VERSION 5.7 ;
  NOWIREEXTENSIONATPIN ON ;
  DIVIDERCHAR "/" ;
  BUSBITCHARS "[]" ;
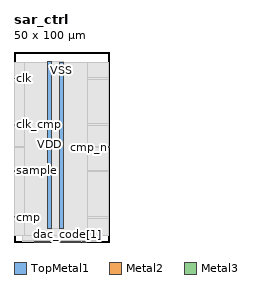
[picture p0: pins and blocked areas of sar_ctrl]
MACRO sar_ctrl
  CLASS BLOCK ;
  FOREIGN sar_ctrl ;
  ORIGIN 0.000 0.000 ;
  SIZE 50.000 BY 100.000 ;
  PIN VDD
    DIRECTION INOUT ;
    USE POWER ;
    PORT
      LAYER TopMetal1 ;
        RECT 17.780 7.340 19.980 95.130 ;
    END
  END VDD
  PIN VSS
    DIRECTION INOUT ;
    USE GROUND ;
    PORT
      LAYER TopMetal1 ;
        RECT 23.980 6.930 26.180 94.720 ;
    END
  END VSS
  PIN busy
    DIRECTION OUTPUT ;
    USE SIGNAL ;
    ANTENNADIFFAREA 0.708600 ;
    PORT
      LAYER Metal2 ;
        RECT 21.400 0.000 21.800 0.400 ;
    END
  END busy
  PIN clk
    DIRECTION INPUT ;
    USE SIGNAL ;
    ANTENNAGATEAREA 1.450800 ;
    PORT
      LAYER Metal3 ;
        RECT 0.000 85.900 0.400 86.300 ;
    END
  END clk
  PIN clk_cmp
    DIRECTION OUTPUT ;
    USE SIGNAL ;
    ANTENNADIFFAREA 0.708600 ;
    PORT
      LAYER Metal3 ;
        RECT 0.000 61.540 0.400 61.940 ;
    END
  END clk_cmp
  PIN cmp
    DIRECTION INPUT ;
    USE SIGNAL ;
    ANTENNAGATEAREA 0.180700 ;
    PORT
      LAYER Metal3 ;
        RECT 0.000 12.820 0.400 13.220 ;
    END
  END cmp
  PIN cmp_n
    DIRECTION INPUT ;
    USE SIGNAL ;
    ANTENNAGATEAREA 0.180700 ;
    PORT
      LAYER Metal3 ;
        RECT 49.600 49.780 50.000 50.180 ;
    END
  END cmp_n
  PIN dac_code[0]
    DIRECTION OUTPUT ;
    USE SIGNAL ;
    ANTENNADIFFAREA 0.708600 ;
    PORT
      LAYER Metal2 ;
        RECT 29.080 0.000 29.480 0.400 ;
    END
  END dac_code[0]
  PIN dac_code[1]
    DIRECTION OUTPUT ;
    USE SIGNAL ;
    ANTENNADIFFAREA 0.708600 ;
    PORT
      LAYER Metal2 ;
        RECT 28.120 0.000 28.520 0.400 ;
    END
  END dac_code[1]
  PIN dac_code[2]
    DIRECTION OUTPUT ;
    USE SIGNAL ;
    ANTENNADIFFAREA 0.708600 ;
    PORT
      LAYER Metal2 ;
        RECT 27.160 0.000 27.560 0.400 ;
    END
  END dac_code[2]
  PIN dac_code[3]
    DIRECTION OUTPUT ;
    USE SIGNAL ;
    ANTENNADIFFAREA 0.708600 ;
    PORT
      LAYER Metal2 ;
        RECT 26.200 0.000 26.600 0.400 ;
    END
  END dac_code[3]
  PIN dac_code[4]
    DIRECTION OUTPUT ;
    USE SIGNAL ;
    ANTENNADIFFAREA 0.708600 ;
    PORT
      LAYER Metal2 ;
        RECT 25.240 0.000 25.640 0.400 ;
    END
  END dac_code[4]
  PIN dac_code[5]
    DIRECTION OUTPUT ;
    USE SIGNAL ;
    ANTENNADIFFAREA 0.708600 ;
    PORT
      LAYER Metal2 ;
        RECT 24.280 0.000 24.680 0.400 ;
    END
  END dac_code[5]
  PIN dac_code[6]
    DIRECTION OUTPUT ;
    USE SIGNAL ;
    ANTENNADIFFAREA 0.708600 ;
    PORT
      LAYER Metal2 ;
        RECT 23.320 0.000 23.720 0.400 ;
    END
  END dac_code[6]
  PIN dac_code[7]
    DIRECTION OUTPUT ;
    USE SIGNAL ;
    ANTENNADIFFAREA 0.708600 ;
    PORT
      LAYER Metal2 ;
        RECT 22.360 0.000 22.760 0.400 ;
    END
  END dac_code[7]
  PIN dac_code_n[0]
    DIRECTION OUTPUT ;
    USE SIGNAL ;
    ANTENNADIFFAREA 0.708600 ;
    PORT
      LAYER Metal2 ;
        RECT 36.760 0.000 37.160 0.400 ;
    END
  END dac_code_n[0]
  PIN dac_code_n[1]
    DIRECTION OUTPUT ;
    USE SIGNAL ;
    ANTENNADIFFAREA 0.708600 ;
    PORT
      LAYER Metal2 ;
        RECT 35.800 0.000 36.200 0.400 ;
    END
  END dac_code_n[1]
  PIN dac_code_n[2]
    DIRECTION OUTPUT ;
    USE SIGNAL ;
    ANTENNADIFFAREA 0.708600 ;
    PORT
      LAYER Metal2 ;
        RECT 34.840 0.000 35.240 0.400 ;
    END
  END dac_code_n[2]
  PIN dac_code_n[3]
    DIRECTION OUTPUT ;
    USE SIGNAL ;
    ANTENNADIFFAREA 0.708600 ;
    PORT
      LAYER Metal2 ;
        RECT 33.880 0.000 34.280 0.400 ;
    END
  END dac_code_n[3]
  PIN dac_code_n[4]
    DIRECTION OUTPUT ;
    USE SIGNAL ;
    ANTENNADIFFAREA 0.708600 ;
    PORT
      LAYER Metal2 ;
        RECT 32.920 0.000 33.320 0.400 ;
    END
  END dac_code_n[4]
  PIN dac_code_n[5]
    DIRECTION OUTPUT ;
    USE SIGNAL ;
    ANTENNADIFFAREA 0.708600 ;
    PORT
      LAYER Metal2 ;
        RECT 31.960 0.000 32.360 0.400 ;
    END
  END dac_code_n[5]
  PIN dac_code_n[6]
    DIRECTION OUTPUT ;
    USE SIGNAL ;
    ANTENNADIFFAREA 0.708600 ;
    PORT
      LAYER Metal2 ;
        RECT 31.000 0.000 31.400 0.400 ;
    END
  END dac_code_n[6]
  PIN dac_code_n[7]
    DIRECTION OUTPUT ;
    USE SIGNAL ;
    ANTENNADIFFAREA 0.708600 ;
    PORT
      LAYER Metal2 ;
        RECT 30.040 0.000 30.440 0.400 ;
    END
  END dac_code_n[7]
  PIN done
    DIRECTION OUTPUT ;
    USE SIGNAL ;
    ANTENNADIFFAREA 0.708600 ;
    PORT
      LAYER Metal2 ;
        RECT 20.440 0.000 20.840 0.400 ;
    END
  END done
  PIN hold
    DIRECTION OUTPUT ;
    USE SIGNAL ;
    ANTENNADIFFAREA 0.708600 ;
    PORT
      LAYER Metal2 ;
        RECT 37.720 0.000 38.120 0.400 ;
    END
  END hold
  PIN result[0]
    DIRECTION OUTPUT ;
    USE SIGNAL ;
    ANTENNADIFFAREA 0.708600 ;
    PORT
      LAYER Metal2 ;
        RECT 12.760 0.000 13.160 0.400 ;
    END
  END result[0]
  PIN result[1]
    DIRECTION OUTPUT ;
    USE SIGNAL ;
    ANTENNADIFFAREA 0.708600 ;
    PORT
      LAYER Metal2 ;
        RECT 13.720 0.000 14.120 0.400 ;
    END
  END result[1]
  PIN result[2]
    DIRECTION OUTPUT ;
    USE SIGNAL ;
    ANTENNADIFFAREA 0.708600 ;
    PORT
      LAYER Metal2 ;
        RECT 14.680 0.000 15.080 0.400 ;
    END
  END result[2]
  PIN result[3]
    DIRECTION OUTPUT ;
    USE SIGNAL ;
    ANTENNADIFFAREA 0.708600 ;
    PORT
      LAYER Metal2 ;
        RECT 15.640 0.000 16.040 0.400 ;
    END
  END result[3]
  PIN result[4]
    DIRECTION OUTPUT ;
    USE SIGNAL ;
    ANTENNADIFFAREA 0.708600 ;
    PORT
      LAYER Metal2 ;
        RECT 16.600 0.000 17.000 0.400 ;
    END
  END result[4]
  PIN result[5]
    DIRECTION OUTPUT ;
    USE SIGNAL ;
    ANTENNADIFFAREA 0.708600 ;
    PORT
      LAYER Metal2 ;
        RECT 17.560 0.000 17.960 0.400 ;
    END
  END result[5]
  PIN result[6]
    DIRECTION OUTPUT ;
    USE SIGNAL ;
    ANTENNADIFFAREA 0.708600 ;
    PORT
      LAYER Metal2 ;
        RECT 18.520 0.000 18.920 0.400 ;
    END
  END result[6]
  PIN result[7]
    DIRECTION OUTPUT ;
    USE SIGNAL ;
    ANTENNADIFFAREA 0.708600 ;
    PORT
      LAYER Metal2 ;
        RECT 19.480 0.000 19.880 0.400 ;
    END
  END result[7]
  PIN rst_n
    DIRECTION INPUT ;
    USE SIGNAL ;
    ANTENNAGATEAREA 0.180700 ;
    PORT
      LAYER Metal2 ;
        RECT 10.840 0.000 11.240 0.400 ;
    END
  END rst_n
  PIN sample
    DIRECTION OUTPUT ;
    USE SIGNAL ;
    ANTENNADIFFAREA 0.708600 ;
    PORT
      LAYER Metal3 ;
        RECT 0.000 37.180 0.400 37.580 ;
    END
  END sample
  PIN start
    DIRECTION INPUT ;
    USE SIGNAL ;
    ANTENNAGATEAREA 0.180700 ;
    PORT
      LAYER Metal2 ;
        RECT 11.800 0.000 12.200 0.400 ;
    END
  END start
  OBS
      LAYER GatPoly ;
        RECT 5.280 7.410 44.640 94.650 ;
      LAYER Metal1 ;
        RECT 5.280 7.340 44.640 94.720 ;
      LAYER Metal2 ;
        RECT 4.215 0.610 44.745 94.645 ;
        RECT 4.215 0.400 10.630 0.610 ;
        RECT 11.450 0.400 11.590 0.610 ;
        RECT 12.410 0.400 12.550 0.610 ;
        RECT 13.370 0.400 13.510 0.610 ;
        RECT 14.330 0.400 14.470 0.610 ;
        RECT 15.290 0.400 15.430 0.610 ;
        RECT 16.250 0.400 16.390 0.610 ;
        RECT 17.210 0.400 17.350 0.610 ;
        RECT 18.170 0.400 18.310 0.610 ;
        RECT 19.130 0.400 19.270 0.610 ;
        RECT 20.090 0.400 20.230 0.610 ;
        RECT 21.050 0.400 21.190 0.610 ;
        RECT 22.010 0.400 22.150 0.610 ;
        RECT 22.970 0.400 23.110 0.610 ;
        RECT 23.930 0.400 24.070 0.610 ;
        RECT 24.890 0.400 25.030 0.610 ;
        RECT 25.850 0.400 25.990 0.610 ;
        RECT 26.810 0.400 26.950 0.610 ;
        RECT 27.770 0.400 27.910 0.610 ;
        RECT 28.730 0.400 28.870 0.610 ;
        RECT 29.690 0.400 29.830 0.610 ;
        RECT 30.650 0.400 30.790 0.610 ;
        RECT 31.610 0.400 31.750 0.610 ;
        RECT 32.570 0.400 32.710 0.610 ;
        RECT 33.530 0.400 33.670 0.610 ;
        RECT 34.490 0.400 34.630 0.610 ;
        RECT 35.450 0.400 35.590 0.610 ;
        RECT 36.410 0.400 36.550 0.610 ;
        RECT 37.370 0.400 37.510 0.610 ;
        RECT 38.330 0.400 44.745 0.610 ;
      LAYER Metal3 ;
        RECT 0.400 86.510 49.600 94.600 ;
        RECT 0.610 85.690 49.600 86.510 ;
        RECT 0.400 62.150 49.600 85.690 ;
        RECT 0.610 61.330 49.600 62.150 ;
        RECT 0.400 50.390 49.600 61.330 ;
        RECT 0.400 49.570 49.390 50.390 ;
        RECT 0.400 37.790 49.600 49.570 ;
        RECT 0.610 36.970 49.600 37.790 ;
        RECT 0.400 13.430 49.600 36.970 ;
        RECT 0.610 12.610 49.600 13.430 ;
        RECT 0.400 3.255 49.600 12.610 ;
      LAYER Metal4 ;
        RECT 5.660 3.215 38.500 94.645 ;
      LAYER Metal5 ;
        RECT 17.915 7.250 26.045 94.810 ;
  END
END sar_ctrl
END LIBRARY

